VERSION 5.7 ;
BUSBITCHARS "[]" ;
DIVIDERCHAR "/" ;

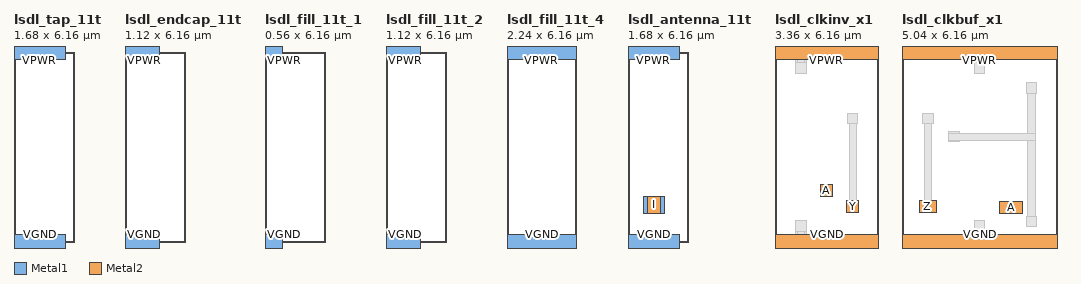
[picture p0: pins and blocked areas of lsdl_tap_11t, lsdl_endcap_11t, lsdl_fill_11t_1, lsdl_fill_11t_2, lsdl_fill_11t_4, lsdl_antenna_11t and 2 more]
MACRO lsdl_tap_11t
 CLASS CORE WELLTAP ;
 FOREIGN lsdl_tap_11t 0 0 ;
 ORIGIN 0 0 ;
 SIZE 1.68 BY 6.16 ;
 SYMMETRY X Y ;
 SITE unit ;
  PIN VPWR
   DIRECTION INOUT ;
   USE POWER ;
   SHAPE ABUTMENT ;
    PORT
       LAYER Metal1 ;
        RECT 0.000 5.920 1.680 6.400 ;
    END
  END VPWR
  PIN VGND
   DIRECTION INOUT ;
   USE GROUND ;
   SHAPE ABUTMENT ;
    PORT
       LAYER Metal1 ;
        RECT 0.000 -0.240 1.680 0.240 ;
    END
  END VGND
END lsdl_tap_11t

MACRO lsdl_endcap_11t
 CLASS ENDCAP PRE ;
 FOREIGN lsdl_endcap_11t 0 0 ;
 ORIGIN 0 0 ;
 SIZE 1.12 BY 6.16 ;
 SYMMETRY X Y ;
 SITE unit ;
  PIN VPWR
   DIRECTION INOUT ;
   USE POWER ;
   SHAPE ABUTMENT ;
    PORT
       LAYER Metal1 ;
        RECT 0.000 5.920 1.120 6.400 ;
    END
  END VPWR
  PIN VGND
   DIRECTION INOUT ;
   USE GROUND ;
   SHAPE ABUTMENT ;
    PORT
       LAYER Metal1 ;
        RECT 0.000 -0.240 1.120 0.240 ;
    END
  END VGND
END lsdl_endcap_11t

MACRO lsdl_fill_11t_1
 CLASS CORE SPACER ;
 FOREIGN lsdl_fill_11t_1 0 0 ;
 ORIGIN 0 0 ;
 SIZE 0.56 BY 6.16 ;
 SYMMETRY X Y ;
 SITE unit ;
  PIN VPWR
   DIRECTION INOUT ;
   USE POWER ;
   SHAPE ABUTMENT ;
    PORT
       LAYER Metal1 ;
        RECT 0.000 5.920 0.560 6.400 ;
    END
  END VPWR
  PIN VGND
   DIRECTION INOUT ;
   USE GROUND ;
   SHAPE ABUTMENT ;
    PORT
       LAYER Metal1 ;
        RECT 0.000 -0.240 0.560 0.240 ;
    END
  END VGND
END lsdl_fill_11t_1

MACRO lsdl_fill_11t_2
 CLASS CORE SPACER ;
 FOREIGN lsdl_fill_11t_2 0 0 ;
 ORIGIN 0 0 ;
 SIZE 1.12 BY 6.16 ;
 SYMMETRY X Y ;
 SITE unit ;
  PIN VPWR
   DIRECTION INOUT ;
   USE POWER ;
   SHAPE ABUTMENT ;
    PORT
       LAYER Metal1 ;
        RECT 0.000 5.920 1.120 6.400 ;
    END
  END VPWR
  PIN VGND
   DIRECTION INOUT ;
   USE GROUND ;
   SHAPE ABUTMENT ;
    PORT
       LAYER Metal1 ;
        RECT 0.000 -0.240 1.120 0.240 ;
    END
  END VGND
END lsdl_fill_11t_2

MACRO lsdl_fill_11t_4
 CLASS CORE SPACER ;
 FOREIGN lsdl_fill_11t_4 0 0 ;
 ORIGIN 0 0 ;
 SIZE 2.24 BY 6.16 ;
 SYMMETRY X Y ;
 SITE unit ;
  PIN VPWR
   DIRECTION INOUT ;
   USE POWER ;
   SHAPE ABUTMENT ;
    PORT
       LAYER Metal1 ;
        RECT 0.000 5.920 2.240 6.400 ;
    END
  END VPWR
  PIN VGND
   DIRECTION INOUT ;
   USE GROUND ;
   SHAPE ABUTMENT ;
    PORT
       LAYER Metal1 ;
        RECT 0.000 -0.240 2.240 0.240 ;
    END
  END VGND
END lsdl_fill_11t_4

MACRO lsdl_antenna_11t
 CLASS CORE ANTENNACELL ;
 FOREIGN lsdl_antenna_11t 0 0 ;
 ORIGIN 0 0 ;
 SIZE 1.68 BY 6.16 ;
 SYMMETRY X Y ;
 SITE unit ;
  PIN I
   DIRECTION INPUT ;
   USE SIGNAL ;
   ANTENNADIFFAREA 0.544 ;
    PORT
       LAYER Metal1 ;
        RECT 0.500 0.940 1.180 1.460 ;
       LAYER Metal2 ;
        RECT 0.620 0.940 1.060 1.460 ;
    END
  END I
  PIN VPWR
   DIRECTION INOUT ;
   USE POWER ;
   SHAPE ABUTMENT ;
    PORT
       LAYER Metal1 ;
        RECT 0.000 5.920 1.680 6.400 ;
    END
  END VPWR
  PIN VGND
   DIRECTION INOUT ;
   USE GROUND ;
   SHAPE ABUTMENT ;
    PORT
       LAYER Metal1 ;
        RECT 0.000 -0.240 1.680 0.240 ;
    END
  END VGND
END lsdl_antenna_11t

MACRO lsdl_clkinv_x1
 CLASS CORE ;
 FOREIGN lsdl_clkinv_x1 0 0 ;
 SIZE 3.36 BY 6.16 ;
 ORIGIN 0 0 ;
 SYMMETRY X Y ;
 SITE unit ;
  PIN VPWR
   DIRECTION INOUT ;
   USE POWER ;
   SHAPE ABUTMENT ;
    PORT
     CLASS CORE ;
       LAYER Metal1 ;
        RECT 0.00000000 5.92000000 3.36000000 6.40000000 ;
       LAYER Metal2 ;
        RECT 0.00000000 5.92000000 3.36000000 6.40000000 ;
    END
  END VPWR

  PIN VGND
   DIRECTION INOUT ;
   USE GROUND ;
   SHAPE ABUTMENT ;
    PORT
     CLASS CORE ;
       LAYER Metal1 ;
        RECT 0.00000000 -0.24000000 3.36000000 0.24000000 ;
       LAYER Metal2 ;
        RECT 0.00000000 -0.24000000 3.36000000 0.24000000 ;
    END
  END VGND

  PIN Y
   DIRECTION OUTPUT ;
   USE SIGNAL ;
   SHAPE ABUTMENT ;
    PORT
     CLASS CORE ;
       LAYER Metal2 ;
        RECT 2.32000000 0.96000000 2.72000000 1.36000000 ;
    END
  END Y

  PIN A
   DIRECTION INPUT ;
   USE SIGNAL ;
   SHAPE ABUTMENT ;
    PORT
     CLASS CORE ;
       LAYER Metal2 ;
        RECT 1.48000000 1.46200000 1.88000000 1.86200000 ;
    END
  END A

 OBS



    LAYER Metal1 ;
     RECT 0.67000000 0.24000000 0.72500000 0.35000000 ;
     RECT 0.95500000 0.24000000 1.01000000 0.35000000 ;
     RECT 0.67000000 5.81000000 0.72500000 5.92000000 ;
     RECT 0.95500000 5.81000000 1.01000000 5.92000000 ;
     RECT 2.32000000 0.96000000 2.72000000 1.36000000 ;
     RECT 2.40500000 1.36000000 2.63500000 3.83000000 ;
     RECT 2.35000000 3.83000000 2.69000000 4.17000000 ;
     RECT 0.67000000 5.47000000 1.01000000 5.81000000 ;
     RECT 0.72500000 5.81000000 0.95500000 5.92000000 ;
     RECT 0.00000000 5.92000000 3.36000000 6.40000000 ;
     RECT 0.00000000 -0.24000000 3.36000000 0.24000000 ;
     RECT 0.72500000 0.24000000 0.95500000 0.35000000 ;
     RECT 0.67000000 0.35000000 1.01000000 0.69000000 ;
     RECT 1.48000000 1.46200000 1.88000000 1.86200000 ;

    LAYER Via1 ;
     RECT 2.39000000 1.03000000 2.65000000 1.29000000 ;
     RECT 0.71000000 6.03000000 0.97000000 6.29000000 ;
     RECT 2.39000000 6.03000000 2.65000000 6.29000000 ;
     RECT 0.71000000 -0.13000000 0.97000000 0.13000000 ;
     RECT 2.39000000 -0.13000000 2.65000000 0.13000000 ;
     RECT 1.55000000 1.53200000 1.81000000 1.79200000 ;

    LAYER Metal2 ;
     RECT 2.32000000 0.96000000 2.72000000 1.36000000 ;
     RECT 0.00000000 5.92000000 3.36000000 6.40000000 ;
     RECT 0.00000000 -0.24000000 3.36000000 0.24000000 ;
     RECT 1.48000000 1.46200000 1.88000000 1.86200000 ;

 END
END lsdl_clkinv_x1

MACRO lsdl_clkbuf_x1
 CLASS CORE ;
 FOREIGN lsdl_clkbuf_x1 0 0 ;
 SIZE 5.04 BY 6.16 ;
 ORIGIN 0 0 ;
 SYMMETRY X Y ;
 SITE unit ;
  PIN VPWR
   DIRECTION INOUT ;
   USE POWER ;
   SHAPE ABUTMENT ;
    PORT
     CLASS CORE ;
       LAYER Metal1 ;
        RECT 0.000 5.920 5.040 6.400 ;
       LAYER Metal2 ;
        RECT 0.000 5.920 5.040 6.400 ;
    END
  END VPWR

  PIN VGND
   DIRECTION INOUT ;
   USE GROUND ;
   SHAPE ABUTMENT ;
    PORT
     CLASS CORE ;
       LAYER Metal1 ;
        RECT 0.000 -0.240 5.040 0.240 ;
       LAYER Metal2 ;
        RECT 0.000 -0.240 5.040 0.240 ;
    END
  END VGND

  PIN Z
   DIRECTION OUTPUT ;
   USE SIGNAL ;
   SHAPE ABUTMENT ;
    PORT
     CLASS CORE ;
       LAYER Metal2 ;
        RECT 0.560 0.960 1.120 1.360 ;
    END
  END Z

  PIN A
   DIRECTION INPUT ;
   USE SIGNAL ;
   SHAPE ABUTMENT ;
    PORT
     CLASS CORE ;
       LAYER Metal2 ;
        RECT 3.160 0.920 3.920 1.320 ;
    END
  END A

 OBS



    LAYER Metal1 ;
     RECT 2.350 0.240 2.405 0.350 ;
     RECT 2.635 0.240 2.690 0.350 ;
     RECT 2.350 5.810 2.405 5.920 ;
     RECT 2.635 5.810 2.690 5.920 ;
     RECT 2.350 5.470 2.690 5.810 ;
     RECT 2.405 5.810 2.635 5.920 ;
     RECT 0.000 5.920 5.040 6.400 ;
     RECT 0.000 -0.240 5.040 0.240 ;
     RECT 2.405 0.240 2.635 0.350 ;
     RECT 2.350 0.350 2.690 0.690 ;
     RECT 4.030 0.490 4.370 0.830 ;
     RECT 1.510 3.245 1.850 3.300 ;
     RECT 4.085 0.830 4.315 3.300 ;
     RECT 1.510 3.300 4.315 3.530 ;
     RECT 1.510 3.530 1.850 3.585 ;
     RECT 4.085 3.530 4.315 4.830 ;
     RECT 4.030 4.830 4.370 5.170 ;
     RECT 3.160 0.920 3.560 1.320 ;
     RECT 0.640 0.960 1.040 1.360 ;
     RECT 0.725 1.360 0.955 3.830 ;
     RECT 0.670 3.830 1.010 4.170 ;

    LAYER Via1 ;
     RECT 0.710 6.030 0.970 6.290 ;
     RECT 2.390 6.030 2.650 6.290 ;
     RECT 4.070 6.030 4.330 6.290 ;
     RECT 0.710 -0.130 0.970 0.130 ;
     RECT 2.390 -0.130 2.650 0.130 ;
     RECT 4.070 -0.130 4.330 0.130 ;
     RECT 3.230 0.990 3.490 1.250 ;
     RECT 0.710 1.030 0.970 1.290 ;

    LAYER Metal2 ;
     RECT 0.000 5.920 5.040 6.400 ;
     RECT 0.000 -0.240 5.040 0.240 ;
     RECT 3.160 0.920 3.560 1.320 ;
     RECT 0.640 0.960 1.040 1.360 ;

 END
END lsdl_clkbuf_x1

END LIBRARY
